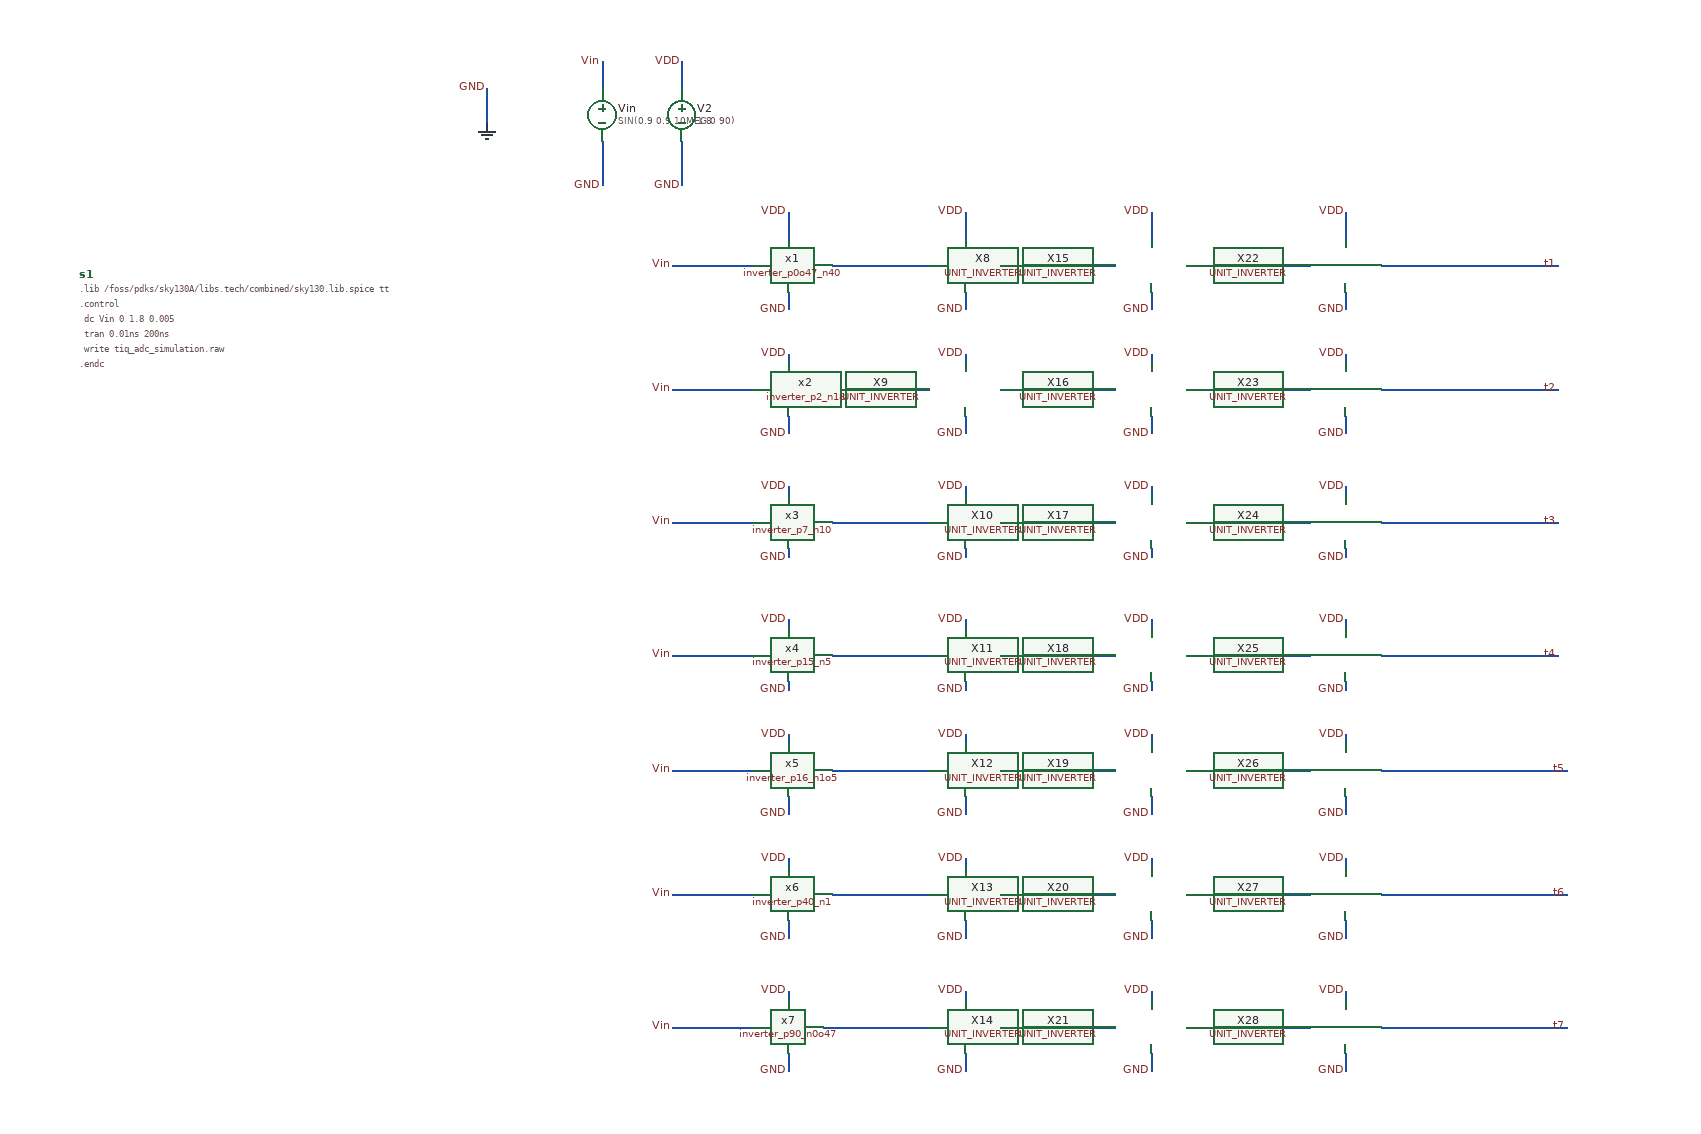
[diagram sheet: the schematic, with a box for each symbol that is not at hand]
v {xschem version=3.4.7 file_version=1.2}
G {}
K {}
V {}
S {}
E {}
N -150 -260 -150 -230 {lab=VDD}
N -150 -170 -150 -120 {lab=GND}
N -240 -170 -240 -120 {lab=GND}
N -240 -260 -240 -230 {lab=Vin}
N -370 -230 -370 -190 {lab=GND}
N -30 -90 -30 -60 {lab=VDD}
N -30 70 -30 80 {lab=VDD}
N -30 0 -30 20 {lab=GND}
N -30 140 -30 160 {lab=GND}
N -30 220 -30 230 {lab=VDD}
N -30 290 -30 300 {lab=GND}
N -30 370 -30 380 {lab=VDD}
N -30 440 -30 450 {lab=GND}
N -30 500 -30 510 {lab=VDD}
N -30 570 -30 590 {lab=GND}
N -30 640 -30 650 {lab=VDD}
N -30 710 -30 730 {lab=GND}
N -30 790 -30 800 {lab=VDD}
N -30 860 -30 880 {lab=GND}
N -160 -30 -70 -30 {lab=Vin}
N -160 830 -70 830 {lab=Vin}
N -160 680 -70 680 {lab=Vin}
N -160 540 -70 540 {lab=Vin}
N -160 410 -70 410 {lab=Vin}
N -160 260 -70 260 {lab=Vin}
N -160 110 -70 110 {lab=Vin}
N 20 -30 90 -30 {lab=#net1}
N 20 110 90 110 {lab=#net2}
N 20 260 90 260 {lab=#net3}
N 20 410 90 410 {lab=#net4}
N 20 680 90 680 {lab=#net5}
N 20 830 90 830 {lab=#net6}
N 90 830 130 830 {lab=#net6}
N 90 680 130 680 {lab=#net5}
N 90 540 130 540 {lab=#net7}
N 90 410 130 410 {lab=#net4}
N 90 260 130 260 {lab=#net3}
N 90 110 130 110 {lab=#net2}
N 90 -30 130 -30 {lab=#net1}
N 760 -30 840 -30 {lab=t1}
N 760 110 840 110 {lab=t2}
N 760 260 840 260 {lab=t3}
N 760 410 840 410 {lab=t4}
N 760 540 850 540 {lab=t5}
N 760 680 850 680 {lab=t6}
N 760 830 850 830 {lab=t7}
N 170 790 170 800 {lab=VDD}
N 170 640 170 650 {lab=VDD}
N 170 500 170 510 {lab=VDD}
N 170 370 170 380 {lab=VDD}
N 170 220 170 230 {lab=VDD}
N 170 70 170 80 {lab=VDD}
N 170 -90 170 -60 {lab=VDD}
N 170 0 170 20 {lab=GND}
N 170 140 170 160 {lab=GND}
N 170 290 170 300 {lab=GND}
N 170 440 170 450 {lab=GND}
N 170 570 170 590 {lab=GND}
N 170 710 170 730 {lab=GND}
N 170 860 170 880 {lab=GND}
N 20 540 90 540 {lab=#net7}
N 10 830 20 830 {lab=#net6}
N 230 110 300 110 {lab=#net8}
N 230 260 300 260 {lab=#net9}
N 230 410 300 410 {lab=#net10}
N 230 680 300 680 {lab=#net11}
N 230 830 300 830 {lab=#net12}
N 300 830 340 830 {lab=#net12}
N 300 680 340 680 {lab=#net11}
N 300 540 340 540 {lab=#net13}
N 300 410 340 410 {lab=#net10}
N 300 260 340 260 {lab=#net9}
N 300 110 340 110 {lab=#net8}
N 300 -30 340 -30 {lab=#net14}
N 380 790 380 800 {lab=VDD}
N 380 640 380 650 {lab=VDD}
N 380 500 380 510 {lab=VDD}
N 380 370 380 380 {lab=VDD}
N 380 220 380 230 {lab=VDD}
N 380 70 380 80 {lab=VDD}
N 380 -90 380 -60 {lab=VDD}
N 380 0 380 20 {lab=GND}
N 380 140 380 160 {lab=GND}
N 380 290 380 300 {lab=GND}
N 380 440 380 450 {lab=GND}
N 380 570 380 590 {lab=GND}
N 380 710 380 730 {lab=GND}
N 380 860 380 880 {lab=GND}
N 230 540 300 540 {lab=#net13}
N 450 110 520 110 {lab=#net15}
N 450 260 520 260 {lab=#net16}
N 450 410 520 410 {lab=#net17}
N 450 680 520 680 {lab=#net18}
N 450 830 520 830 {lab=#net19}
N 520 830 560 830 {lab=#net19}
N 520 680 560 680 {lab=#net18}
N 520 540 560 540 {lab=#net20}
N 520 410 560 410 {lab=#net17}
N 520 260 560 260 {lab=#net16}
N 520 110 560 110 {lab=#net15}
N 520 -30 560 -30 {lab=#net21}
N 600 790 600 800 {lab=VDD}
N 600 640 600 650 {lab=VDD}
N 600 500 600 510 {lab=VDD}
N 600 370 600 380 {lab=VDD}
N 600 220 600 230 {lab=VDD}
N 600 70 600 80 {lab=VDD}
N 600 -90 600 -60 {lab=VDD}
N 600 0 600 20 {lab=GND}
N 600 140 600 160 {lab=GND}
N 600 290 600 300 {lab=GND}
N 600 440 600 450 {lab=GND}
N 600 570 600 590 {lab=GND}
N 600 710 600 730 {lab=GND}
N 600 860 600 880 {lab=GND}
N 450 540 520 540 {lab=#net20}
N 640 -30 760 -30 {lab=t1}
N 640 110 760 110 {lab=t2}
N 640 260 760 260 {lab=t3}
N 640 410 760 410 {lab=t4}
N 640 540 760 540 {lab=t5}
N 640 680 760 680 {lab=t6}
N 640 830 760 830 {lab=t7}
N 420 830 450 830 {lab=#net19}
N 420 680 450 680 {lab=#net18}
N 420 540 450 540 {lab=#net20}
N 420 410 450 410 {lab=#net17}
N 420 260 450 260 {lab=#net16}
N 420 110 450 110 {lab=#net15}
N 420 -30 520 -30 {lab=#net21}
N 210 -30 300 -30 {lab=#net14}
N 210 110 230 110 {lab=#net8}
N 210 260 230 260 {lab=#net9}
N 210 410 230 410 {lab=#net10}
N 210 540 230 540 {lab=#net13}
N 210 680 230 680 {lab=#net11}
N 210 830 230 830 {lab=#net12}
C {vsource.sym} -240 -200 0 0 {name=Vin value="SIN(0.9 0.9 10MEG 0 90)" savecurrent=false}
C {vsource.sym} -150 -200 0 0 {name=V2 value=1.8 savecurrent=false}
C {gnd.sym} -370 -190 0 0 {name=l1 lab=GND}
C {lab_wire.sym} -370 -230 0 0 {name=p1 sig_type=std_logic lab=GND}
C {lab_wire.sym} -240 -120 0 0 {name=p2 sig_type=std_logic lab=GND}
C {lab_wire.sym} -150 -120 0 0 {name=p3 sig_type=std_logic lab=GND}
C {lab_wire.sym} -240 -260 0 0 {name=p4 sig_type=std_logic lab=Vin}
C {lab_wire.sym} -150 -260 0 0 {name=p5 sig_type=std_logic lab=VDD}
C {lab_wire.sym} -30 -90 0 0 {name=p6 sig_type=std_logic lab=VDD}
C {lab_wire.sym} -30 70 0 0 {name=p7 sig_type=std_logic lab=VDD}
C {lab_wire.sym} -30 20 0 0 {name=p8 sig_type=std_logic lab=GND}
C {lab_wire.sym} -30 160 0 0 {name=p9 sig_type=std_logic lab=GND}
C {lab_wire.sym} -30 220 0 0 {name=p10 sig_type=std_logic lab=VDD}
C {lab_wire.sym} -30 300 0 0 {name=p11 sig_type=std_logic lab=GND}
C {lab_wire.sym} -30 370 0 0 {name=p12 sig_type=std_logic lab=VDD}
C {lab_wire.sym} -30 450 0 0 {name=p13 sig_type=std_logic lab=GND}
C {lab_wire.sym} -30 500 0 0 {name=p14 sig_type=std_logic lab=VDD}
C {lab_wire.sym} -30 590 0 0 {name=p15 sig_type=std_logic lab=GND}
C {lab_wire.sym} -30 640 0 0 {name=p16 sig_type=std_logic lab=VDD}
C {lab_wire.sym} -30 730 0 0 {name=p17 sig_type=std_logic lab=GND}
C {lab_wire.sym} -30 790 0 0 {name=p18 sig_type=std_logic lab=VDD}
C {lab_wire.sym} -30 880 0 0 {name=p19 sig_type=std_logic lab=GND}
C {lab_wire.sym} -160 -30 0 0 {name=p20 sig_type=std_logic lab=Vin}
C {code_shown.sym} -830 -20 0 0 {name=s1 only_toplevel=false value=
"
.lib /foss/pdks/sky130A/libs.tech/combined/sky130.lib.spice tt

.control
	dc Vin 0 1.8 0.005
	tran 0.01ns 200ns
	write tiq_adc_simulation.raw
.endc
"
}
C {lab_wire.sym} -160 110 0 0 {name=p30 sig_type=std_logic lab=Vin}
C {lab_wire.sym} -160 260 0 0 {name=p31 sig_type=std_logic lab=Vin}
C {lab_wire.sym} -160 410 0 0 {name=p32 sig_type=std_logic lab=Vin}
C {lab_wire.sym} -160 540 0 0 {name=p33 sig_type=std_logic lab=Vin}
C {lab_wire.sym} -160 680 0 0 {name=p34 sig_type=std_logic lab=Vin}
C {lab_wire.sym} -160 830 0 0 {name=p35 sig_type=std_logic lab=Vin}
C {lab_wire.sym} 840 -30 0 0 {name=p21 sig_type=std_logic lab=t1}
C {lab_wire.sym} 840 110 0 0 {name=p22 sig_type=std_logic lab=t2}
C {lab_wire.sym} 840 260 0 0 {name=p23 sig_type=std_logic lab=t3}
C {lab_wire.sym} 840 410 0 0 {name=p24 sig_type=std_logic lab=t4}
C {lab_wire.sym} 850 540 0 0 {name=p25 sig_type=std_logic lab=t5}
C {lab_wire.sym} 850 680 0 0 {name=p26 sig_type=std_logic lab=t6}
C {lab_wire.sym} 850 830 0 0 {name=p27 sig_type=std_logic lab=t7}
C {/foss/designs/analog-circuit-design/sky25a-TIQ_ADC/xschem/UNIT_INVERTER.sym} 80 -30 0 0 {name=X8 w_n=0.47 w_p=1}
C {/foss/designs/analog-circuit-design/sky25a-TIQ_ADC/xschem/UNIT_INVERTER.sym} 80 110 0 0 {name=X9 w_n=0.47 w_p=1}
C {/foss/designs/analog-circuit-design/sky25a-TIQ_ADC/xschem/UNIT_INVERTER.sym} 80 260 0 0 {name=X10 w_n=0.47 w_p=1}
C {/foss/designs/analog-circuit-design/sky25a-TIQ_ADC/xschem/UNIT_INVERTER.sym} 80 410 0 0 {name=X11 w_n=0.47 w_p=1}
C {/foss/designs/analog-circuit-design/sky25a-TIQ_ADC/xschem/UNIT_INVERTER.sym} 80 540 0 0 {name=X12 w_n=0.47 w_p=1}
C {/foss/designs/analog-circuit-design/sky25a-TIQ_ADC/xschem/UNIT_INVERTER.sym} 80 680 0 0 {name=X13 w_n=0.47 w_p=1}
C {/foss/designs/analog-circuit-design/sky25a-TIQ_ADC/xschem/UNIT_INVERTER.sym} 80 830 0 0 {name=X14 w_n=0.47 w_p=1}
C {lab_wire.sym} 170 -90 0 0 {name=p28 sig_type=std_logic lab=VDD}
C {lab_wire.sym} 170 70 0 0 {name=p29 sig_type=std_logic lab=VDD}
C {lab_wire.sym} 170 220 0 0 {name=p36 sig_type=std_logic lab=VDD}
C {lab_wire.sym} 170 370 0 0 {name=p37 sig_type=std_logic lab=VDD}
C {lab_wire.sym} 170 500 0 0 {name=p38 sig_type=std_logic lab=VDD}
C {lab_wire.sym} 170 640 0 0 {name=p39 sig_type=std_logic lab=VDD}
C {lab_wire.sym} 170 790 0 0 {name=p40 sig_type=std_logic lab=VDD}
C {lab_wire.sym} 170 20 0 0 {name=p41 sig_type=std_logic lab=GND}
C {lab_wire.sym} 170 160 0 0 {name=p42 sig_type=std_logic lab=GND}
C {lab_wire.sym} 170 300 0 0 {name=p43 sig_type=std_logic lab=GND}
C {lab_wire.sym} 170 450 0 0 {name=p44 sig_type=std_logic lab=GND}
C {lab_wire.sym} 170 590 0 0 {name=p45 sig_type=std_logic lab=GND}
C {lab_wire.sym} 170 730 0 0 {name=p46 sig_type=std_logic lab=GND}
C {lab_wire.sym} 170 880 0 0 {name=p47 sig_type=std_logic lab=GND}
C {/foss/designs/analog-circuit-design/sky25a-TIQ_ADC/xschem/INVERTER_SIZES/inverter_p15_n5.sym} -30 410 0 0 {name=x4}
C {/foss/designs/analog-circuit-design/sky25a-TIQ_ADC/xschem/INVERTER_SIZES/inverter_p16_n1o5.sym} -30 540 0 0 {name=x5}
C {/foss/designs/analog-circuit-design/sky25a-TIQ_ADC/xschem/INVERTER_SIZES/inverter_p40_n1.sym} -30 680 0 0 {name=x6}
C {/foss/designs/analog-circuit-design/sky25a-TIQ_ADC/xschem/INVERTER_SIZES/inverter_p2_n18.sym} -40 110 0 0 {name=x2}
C {/foss/designs/analog-circuit-design/sky25a-TIQ_ADC/xschem/INVERTER_SIZES/inverter_p7_n10.sym} -30 260 0 0 {name=x3}
C {/foss/designs/analog-circuit-design/sky25a-TIQ_ADC/xschem/INVERTER_SIZES/inverter_p90_n0o47.sym} -30 830 0 0 {name=x7}
C {/foss/designs/analog-circuit-design/sky25a-TIQ_ADC/xschem/INVERTER_SIZES/inverter_p0o47_n40.sym} -30 -30 0 0 {name=x1}
C {/foss/designs/analog-circuit-design/sky25a-TIQ_ADC/xschem/UNIT_INVERTER.sym} 290 -30 0 0 {name=X15 w_n=0.47 w_p=1}
C {/foss/designs/analog-circuit-design/sky25a-TIQ_ADC/xschem/UNIT_INVERTER.sym} 290 110 0 0 {name=X16 w_n=0.47 w_p=1}
C {/foss/designs/analog-circuit-design/sky25a-TIQ_ADC/xschem/UNIT_INVERTER.sym} 290 260 0 0 {name=X17 w_n=0.47 w_p=1}
C {/foss/designs/analog-circuit-design/sky25a-TIQ_ADC/xschem/UNIT_INVERTER.sym} 290 410 0 0 {name=X18 w_n=0.47 w_p=1}
C {/foss/designs/analog-circuit-design/sky25a-TIQ_ADC/xschem/UNIT_INVERTER.sym} 290 540 0 0 {name=X19 w_n=0.47 w_p=1}
C {/foss/designs/analog-circuit-design/sky25a-TIQ_ADC/xschem/UNIT_INVERTER.sym} 290 680 0 0 {name=X20 w_n=0.47 w_p=1}
C {/foss/designs/analog-circuit-design/sky25a-TIQ_ADC/xschem/UNIT_INVERTER.sym} 290 830 0 0 {name=X21 w_n=0.47 w_p=1}
C {lab_wire.sym} 380 -90 0 0 {name=p48 sig_type=std_logic lab=VDD}
C {lab_wire.sym} 380 70 0 0 {name=p49 sig_type=std_logic lab=VDD}
C {lab_wire.sym} 380 220 0 0 {name=p50 sig_type=std_logic lab=VDD}
C {lab_wire.sym} 380 370 0 0 {name=p51 sig_type=std_logic lab=VDD}
C {lab_wire.sym} 380 500 0 0 {name=p52 sig_type=std_logic lab=VDD}
C {lab_wire.sym} 380 640 0 0 {name=p53 sig_type=std_logic lab=VDD}
C {lab_wire.sym} 380 790 0 0 {name=p54 sig_type=std_logic lab=VDD}
C {lab_wire.sym} 380 20 0 0 {name=p55 sig_type=std_logic lab=GND}
C {lab_wire.sym} 380 160 0 0 {name=p56 sig_type=std_logic lab=GND}
C {lab_wire.sym} 380 300 0 0 {name=p57 sig_type=std_logic lab=GND}
C {lab_wire.sym} 380 450 0 0 {name=p58 sig_type=std_logic lab=GND}
C {lab_wire.sym} 380 590 0 0 {name=p59 sig_type=std_logic lab=GND}
C {lab_wire.sym} 380 730 0 0 {name=p60 sig_type=std_logic lab=GND}
C {lab_wire.sym} 380 880 0 0 {name=p61 sig_type=std_logic lab=GND}
C {/foss/designs/analog-circuit-design/sky25a-TIQ_ADC/xschem/UNIT_INVERTER.sym} 510 -30 0 0 {name=X22 w_n=0.47 w_p=1}
C {/foss/designs/analog-circuit-design/sky25a-TIQ_ADC/xschem/UNIT_INVERTER.sym} 510 110 0 0 {name=X23 w_n=0.47 w_p=1}
C {/foss/designs/analog-circuit-design/sky25a-TIQ_ADC/xschem/UNIT_INVERTER.sym} 510 260 0 0 {name=X24 w_n=0.47 w_p=1}
C {/foss/designs/analog-circuit-design/sky25a-TIQ_ADC/xschem/UNIT_INVERTER.sym} 510 410 0 0 {name=X25 w_n=0.47 w_p=1}
C {/foss/designs/analog-circuit-design/sky25a-TIQ_ADC/xschem/UNIT_INVERTER.sym} 510 540 0 0 {name=X26 w_n=0.47 w_p=1}
C {/foss/designs/analog-circuit-design/sky25a-TIQ_ADC/xschem/UNIT_INVERTER.sym} 510 680 0 0 {name=X27 w_n=0.47 w_p=1}
C {/foss/designs/analog-circuit-design/sky25a-TIQ_ADC/xschem/UNIT_INVERTER.sym} 510 830 0 0 {name=X28 w_n=0.47 w_p=1}
C {lab_wire.sym} 600 -90 0 0 {name=p62 sig_type=std_logic lab=VDD}
C {lab_wire.sym} 600 70 0 0 {name=p63 sig_type=std_logic lab=VDD}
C {lab_wire.sym} 600 220 0 0 {name=p64 sig_type=std_logic lab=VDD}
C {lab_wire.sym} 600 370 0 0 {name=p65 sig_type=std_logic lab=VDD}
C {lab_wire.sym} 600 500 0 0 {name=p66 sig_type=std_logic lab=VDD}
C {lab_wire.sym} 600 640 0 0 {name=p67 sig_type=std_logic lab=VDD}
C {lab_wire.sym} 600 790 0 0 {name=p68 sig_type=std_logic lab=VDD}
C {lab_wire.sym} 600 20 0 0 {name=p69 sig_type=std_logic lab=GND}
C {lab_wire.sym} 600 160 0 0 {name=p70 sig_type=std_logic lab=GND}
C {lab_wire.sym} 600 300 0 0 {name=p71 sig_type=std_logic lab=GND}
C {lab_wire.sym} 600 450 0 0 {name=p72 sig_type=std_logic lab=GND}
C {lab_wire.sym} 600 590 0 0 {name=p73 sig_type=std_logic lab=GND}
C {lab_wire.sym} 600 730 0 0 {name=p74 sig_type=std_logic lab=GND}
C {lab_wire.sym} 600 880 0 0 {name=p75 sig_type=std_logic lab=GND}
